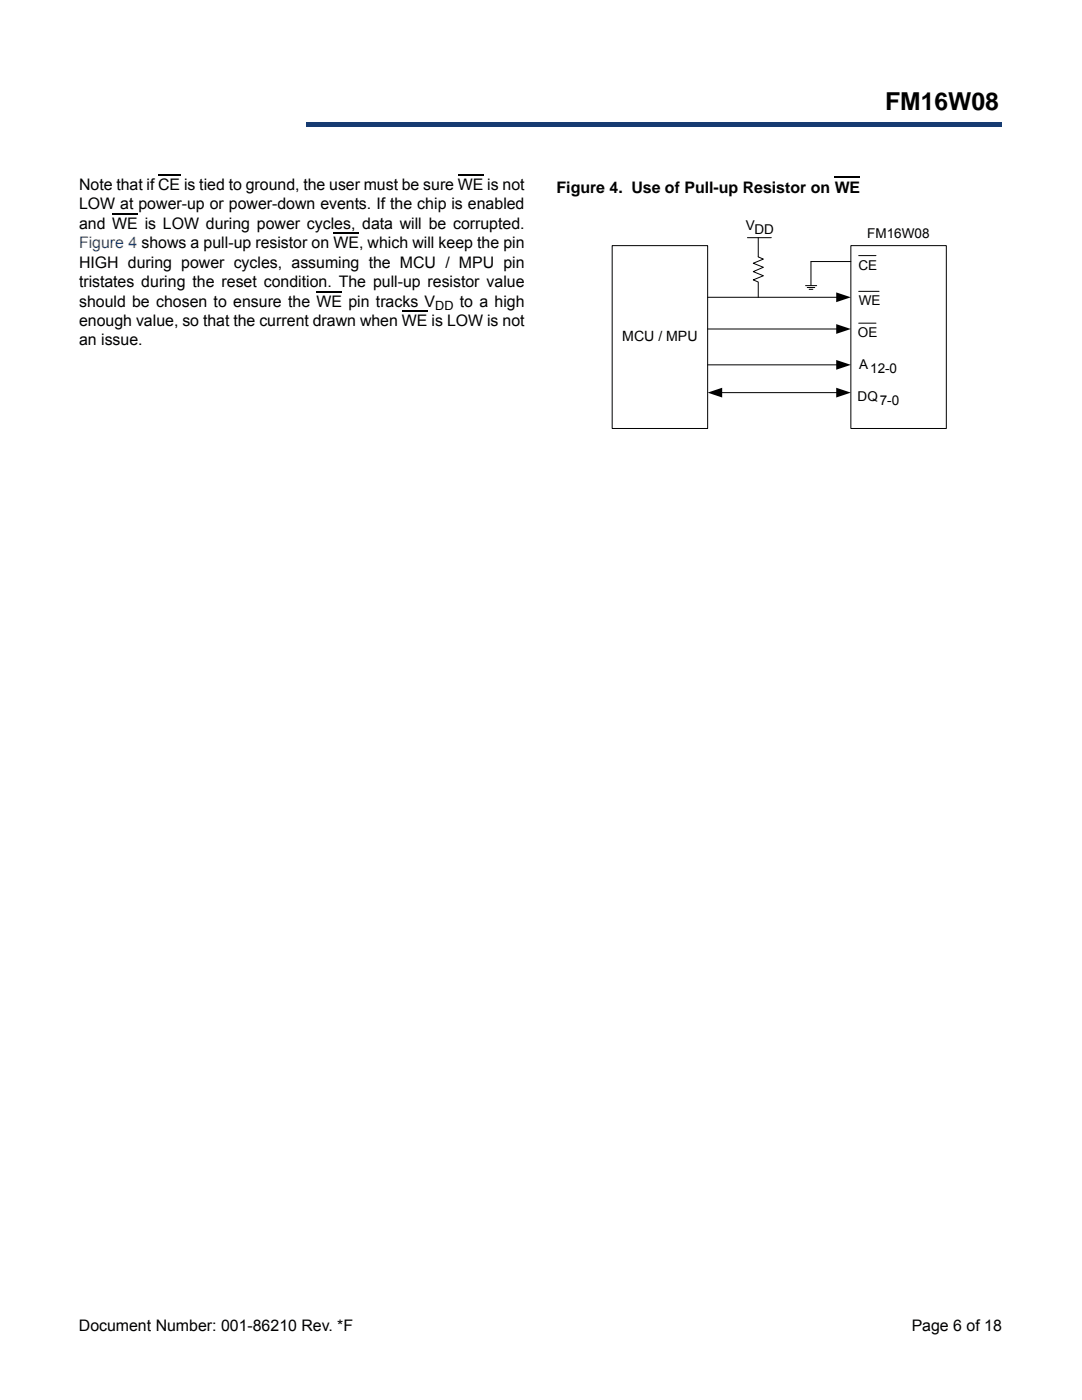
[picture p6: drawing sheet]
<svg xmlns="http://www.w3.org/2000/svg" width="216mm" height="279mm" viewBox="0 0 216 279" stroke-linecap="round" stroke-linejoin="round" font-family="sans-serif">
<defs><g id="words">
<text font-size="4.9" x="176.6" y="22">FM16W08</text>
<g font-size="3.2">
<text x="15.8" y="41.8">LOW at power-up or power-down events. If the chip is enabled</text>
<text x="15.8" y="37.9">Note that if CE is tied to ground, the user must be sure WE is not</text>
<text x="111" y="38.6">Figure 4. Use of Pull-up Resistor on WE</text>
<text x="15.8" y="45.6">and WE is LOW during power cycles, data will be corrupted.</text>
<text x="15.8" y="53.4">HIGH during power cycles, assuming the MCU / MPU pin</text>
<text x="15.8" y="57.3">tristates during the reset condition. The pull-up resistor value</text>
<text x="15.8" y="65">enough value, so that the current drawn when WE is LOW is not</text>
<text x="15.8" y="61.2">should be chosen to ensure the WE pin tracks V</text>
<text x="91.8" y="61.2">to a high</text>
<text x="15.8" y="68.9">an issue.</text>
<text x="15.7" y="265.6">Document Number: 001-86210 Rev. *F</text>
<text x="181.9" y="265.6">Page 6 of 18</text>
</g>
<text font-size="3.2" fill="#1f52a1" x="15.8" y="49.5">Figure 4 shows a pull-up resistor on WE, which will keep the pin</text>
<text font-size="2.8" x="124.2" y="68.1">MCU / MPU</text>
<g font-size="2.7">
<text x="148.8" y="45.8">V</text>
<text x="150.6" y="46.7">DD</text>
<text x="173.1" y="47.5">FM16W08</text>
<text x="171.3" y="53.8">CE</text>
<text x="171.4" y="60.9">WE</text>
<text x="171.2" y="67.3">OE</text>
<text x="171.4" y="73.6">A</text>
<text x="173.6" y="74.4">12-0</text>
<text x="171.1" y="80">DQ</text>
<text x="175.6" y="80.8">7-0</text>
</g>
<text font-size="2.5" x="86.8" y="62">DD</text>
</g></defs>
<path d="M61 24.4h138.8v.9h-138.8z" fill="#163b71"/>
<path d="M61 24.4h138.9" fill="none" stroke="#163b71" stroke-width=".2"/>
<path d="M199.7 24.4h.2v1h-.2z" fill="#163b71"/>
<path d="M61 25.3h138.8" fill="none" stroke="#163b71" stroke-width=".2"/>
<path d="M61 24.3h.1v1h-.1z" fill="#163b71"/>
<path d="M15.8 8.6h45.2v18h-45.2z" fill="#fff"/>
<path d="M31.6 34.9h4.4M91.4 34.9h5.1M22.4 42.6h5.1M63.2 58.2h5.1M66.5 46.5h5.1M80.2 62.1h5.1" fill="none" stroke="#000" stroke-width=".23"/>
<path d="M166.5 35.3h5.1" fill="none" stroke="#000" stroke-width=".34"/>
<path d="M121.7 42.6h67.6v43.4h-67.6z" fill="#fff"/>
<g fill="none" stroke="#000" stroke-width=".2">
<path d="M122.2 49h19v36.5h-19zM141.2 59.3h25.9M149.1 47.4h4.8M151.3 47.4v3.9l1 .4-2 .8 2 .8-2 .9 2 .8-2 .9 1 .4v3M160.7 57h2.3M161.1 57.4h1.5M161.5 57.7h.7M169.8 49h19v36.5h-19zM169.8 52.2h-8v4.8M171.3 51h3.5M171.3 58.1h4.1M141.2 65.7h25.9"/>
<path d="M141.2 72.8h25.9M143.9 78.4h23.2M171.3 64.5h3.5"/>
</g>
<path d="M166.9 58.4l2.9 .9-2.9 1zM141.2 78.4l2.9-1v1.9zM166.9 64.7l2.9 1-2.9 .9zM166.9 71.8l2.9 1-2.9 1zM166.9 77.4l2.9 1-2.9 .9z" fill="#000"/>
<use href="#words"/>
</svg>
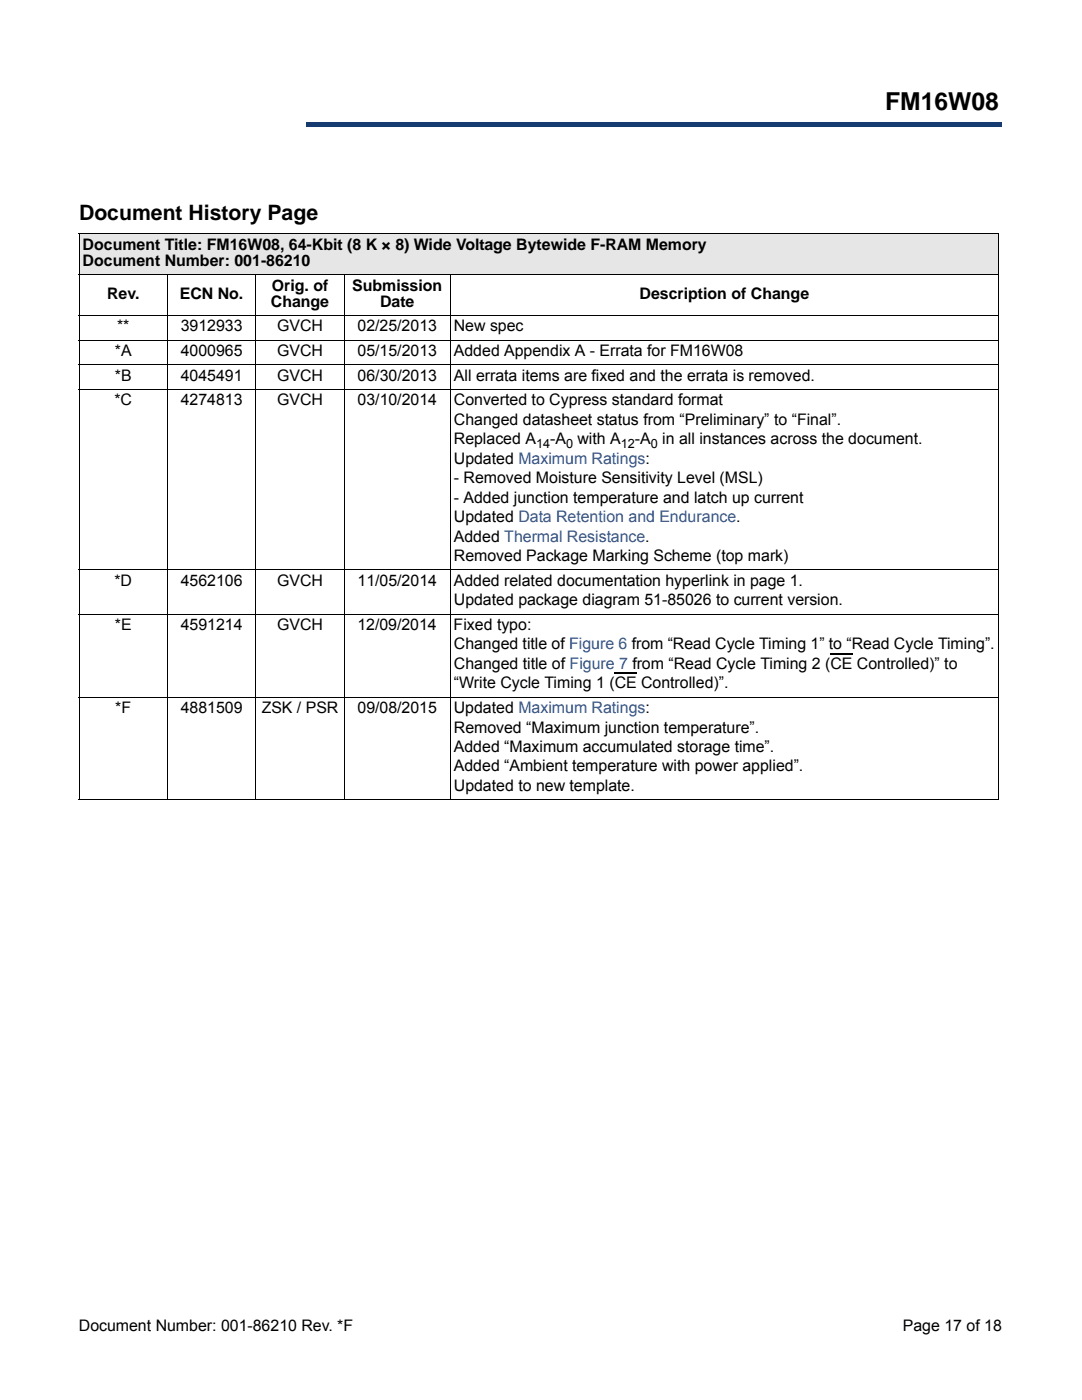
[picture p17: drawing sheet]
<svg xmlns="http://www.w3.org/2000/svg" width="216mm" height="279mm" viewBox="0 0 216 279" stroke-linecap="round" stroke-linejoin="round" font-family="sans-serif">
<defs><g id="words">
<text font-size="4.9" x="176.6" y="22">FM16W08</text>
<text font-size="4.2" x="15.8" y="43.9">Document History Page</text>
<g font-size="3.2">
<text x="16.5" y="49.9">Document Title: FM16W08, 64-Kbit (8 K × 8) Wide Voltage Bytewide F-RAM Memory</text>
<text x="16.5" y="53">Document Number: 001-86210</text>
<text x="21.4" y="59.6">Rev.</text>
<text x="35.9" y="59.6">ECN No.</text>
<text x="54.2" y="58">Orig. of</text>
<text x="70.3" y="58">Submission</text>
<text x="127.6" y="59.6">Description of Change</text>
<text x="54.1" y="61.2">Change</text>
<text x="75.8" y="61.2">Date</text>
<text x="22.9" y="71.1">*A</text>
<text x="23.4" y="66.1">**</text>
<text x="36.1" y="66.1">3912933</text>
<text x="36.1" y="71.1">4000965</text>
<text x="55.3" y="66.1">GVCH</text>
<text x="55.3" y="71.1">GVCH</text>
<text x="71.4" y="66.1">02/25/2013</text>
<text x="71.4" y="71.1">05/15/2013</text>
<text x="90.6" y="66.1">New spec</text>
<text x="90.6" y="71.1">Added Appendix A - Errata for FM16W08</text>
<text x="22.9" y="76">*B</text>
<text x="36.1" y="76">4045491</text>
<text x="55.3" y="76">GVCH</text>
<text x="71.4" y="76">06/30/2013</text>
<text x="90.6" y="76">All errata items are fixed and the errata is removed.</text>
<text x="22.8" y="80.9">*C</text>
<text x="36.1" y="80.9">4274813</text>
<text x="55.3" y="80.9">GVCH</text>
<text x="71.4" y="80.9">03/10/2014</text>
<text x="90.6" y="80.9">Converted to Cypress standard format</text>
<text x="90.6" y="84.8">Changed datasheet status from “Preliminary” to “Final”.</text>
<text x="90.6" y="88.7">Replaced A</text>
<text x="109.8" y="88.7">-A</text>
<text x="115.2" y="88.7">with A</text>
<text x="126.7" y="88.7">-A</text>
<text x="132.1" y="88.7">in all instances across the document.</text>
<text x="90.6" y="92.6">Updated Maximum Ratings:</text>
<text x="90.6" y="96.5">- Removed Moisture Sensitivity Level (MSL)</text>
<text x="90.6" y="100.3">- Added junction temperature and latch up current</text>
<text x="90.6" y="104.2">Updated Data Retention and Endurance.</text>
<text x="90.6" y="112">Removed Package Marking Scheme (top mark)</text>
<text x="90.6" y="108.1">Added Thermal Resistance.</text>
<text x="22.8" y="116.9">*D</text>
<text x="36.1" y="116.9">4562106</text>
<text x="55.3" y="116.9">GVCH</text>
<text x="71.4" y="116.9">11/05/2014</text>
<text x="90.6" y="116.9">Added related documentation hyperlink in page 1.</text>
<text x="22.9" y="125.7">*E</text>
<text x="36.1" y="125.7">4591214</text>
<text x="55.3" y="125.7">GVCH</text>
<text x="71.3" y="125.7">12/09/2014</text>
<text x="90.5" y="125.7">Fixed typo:</text>
<text x="90.6" y="120.8">Updated package diagram 51-85026 to current version.</text>
<text x="90.6" y="129.6">Changed title of Figure 6 from “Read Cycle Timing 1” to “Read Cycle Timing”.</text>
<text x="90.6" y="137.4">“Write Cycle Timing 1 (CE Controlled)”.</text>
<text x="90.6" y="133.5">Changed title of Figure 7 from “Read Cycle Timing 2 (CE Controlled)” to</text>
<text x="23" y="142.3">*F</text>
<text x="36.1" y="142.3">4881509</text>
<text x="52.2" y="142.3">ZSK / PSR</text>
<text x="71.3" y="142.3">09/08/2015</text>
<text x="90.5" y="142.3">Updated Maximum Ratings:</text>
<text x="90.6" y="146.2">Removed “Maximum junction temperature”.</text>
<text x="90.6" y="150.1">Added “Maximum accumulated storage time”.</text>
<text x="90.6" y="153.9">Added “Ambient temperature with power applied”.</text>
<text x="90.6" y="157.8">Updated to new template.</text>
<text x="15.7" y="265.6">Document Number: 001-86210 Rev. *F</text>
<text x="180.1" y="265.6">Page 17 of 18</text>
</g>
<g font-size="2.5">
<text x="107" y="89.5">14</text>
<text x="112.9" y="89.5">0</text>
<text x="123.9" y="89.5">12</text>
<text x="129.9" y="89.5">0</text>
</g>
</g></defs>
<path d="M61 24.4h138.8v.9h-138.8z" fill="#163b71"/>
<path d="M61 24.4h138.9" fill="none" stroke="#163b71" stroke-width=".2"/>
<path d="M199.7 24.4h.2v1h-.2z" fill="#163b71"/>
<path d="M61 25.3h138.8" fill="none" stroke="#163b71" stroke-width=".2"/>
<path d="M61 24.3h.1v1h-.1z" fill="#163b71"/>
<path d="M15.8 8.6h45.2v18h-45.2z" fill="#fff"/>
<path d="M15.8 46.7h183.4v8.1h-183.4z" fill="#e6e6e6"/>
<g fill="#fff">
<path d="M15.8 54.8h17.6v8.1h-17.6z"/>
<path d="M33.4 54.8h17.7v8.1h-17.7z"/>
<path d="M51.1 54.8h17.6v8.1h-17.6z"/>
<path d="M68.7 54.8h21.2v8.1h-21.2z"/>
<path d="M89.9 54.8h109.3v8.1h-109.3z"/>
</g>
<path d="M122.6 134.4h4.4M165.7 130.5h4.4" fill="none" stroke="#000" stroke-width=".23"/>
<g fill="none" stroke="#000" stroke-width=".2">
<path d="M15.7 46.7h183.6M15.7 54.8h183.6M15.8 46.8v112.7M33.4 54.7v105M51.1 54.7v105M68.7 54.7v105M89.9 54.7v105M199.2 46.8v112.7M15.7 62.9h183.6M15.7 67.9h183.6M15.7 72.8h183.6M15.7 77.7h183.6"/>
<path d="M15.7 113.7h183.6M15.7 122.6h183.6M15.7 139.1h183.6M15.7 159.6h183.6"/>
</g>
<use href="#words"/>
</svg>
